VERSION 5.7 ;
BUSBITCHARS "[]" ;
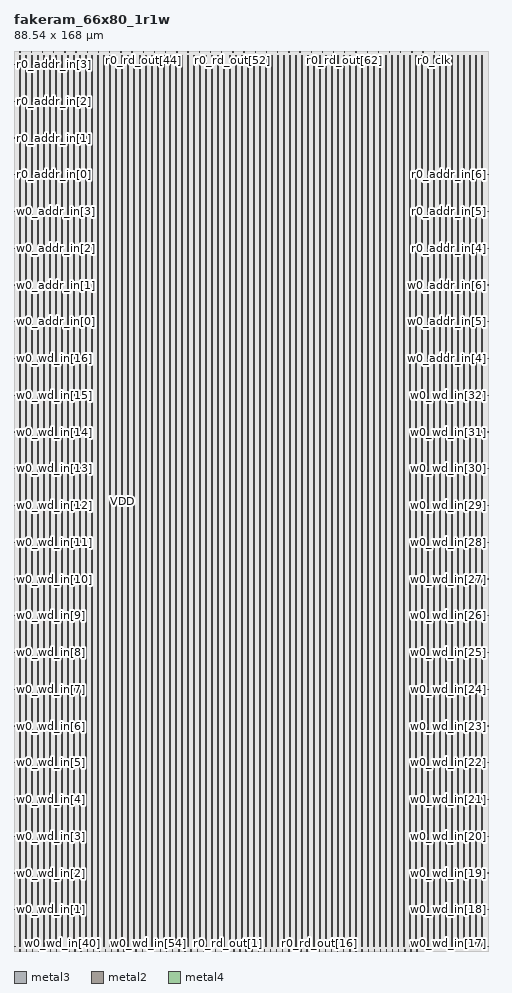
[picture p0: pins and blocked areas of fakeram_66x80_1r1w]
MACRO fakeram_66x80_1r1w
  FOREIGN fakeram_66x80_1r1w 0 0 ;
  SYMMETRY X Y R90 ;
  SIZE 88.540 BY 168.000 ;
  CLASS BLOCK ;
  PIN w0_wd_in[0]
    DIRECTION INPUT ;
    USE SIGNAL ;
    SHAPE ABUTMENT ;
    PORT
      LAYER metal3 ;
      RECT 0.000 0.805 0.210 0.875 ;
    END
  END w0_wd_in[0]
  PIN w0_wd_in[1]
    DIRECTION INPUT ;
    USE SIGNAL ;
    SHAPE ABUTMENT ;
    PORT
      LAYER metal3 ;
      RECT 0.000 7.665 0.210 7.735 ;
    END
  END w0_wd_in[1]
  PIN w0_wd_in[2]
    DIRECTION INPUT ;
    USE SIGNAL ;
    SHAPE ABUTMENT ;
    PORT
      LAYER metal3 ;
      RECT 0.000 14.525 0.210 14.595 ;
    END
  END w0_wd_in[2]
  PIN w0_wd_in[3]
    DIRECTION INPUT ;
    USE SIGNAL ;
    SHAPE ABUTMENT ;
    PORT
      LAYER metal3 ;
      RECT 0.000 21.385 0.210 21.455 ;
    END
  END w0_wd_in[3]
  PIN w0_wd_in[4]
    DIRECTION INPUT ;
    USE SIGNAL ;
    SHAPE ABUTMENT ;
    PORT
      LAYER metal3 ;
      RECT 0.000 28.245 0.210 28.315 ;
    END
  END w0_wd_in[4]
  PIN w0_wd_in[5]
    DIRECTION INPUT ;
    USE SIGNAL ;
    SHAPE ABUTMENT ;
    PORT
      LAYER metal3 ;
      RECT 0.000 35.105 0.210 35.175 ;
    END
  END w0_wd_in[5]
  PIN w0_wd_in[6]
    DIRECTION INPUT ;
    USE SIGNAL ;
    SHAPE ABUTMENT ;
    PORT
      LAYER metal3 ;
      RECT 0.000 41.965 0.210 42.035 ;
    END
  END w0_wd_in[6]
  PIN w0_wd_in[7]
    DIRECTION INPUT ;
    USE SIGNAL ;
    SHAPE ABUTMENT ;
    PORT
      LAYER metal3 ;
      RECT 0.000 48.825 0.210 48.895 ;
    END
  END w0_wd_in[7]
  PIN w0_wd_in[8]
    DIRECTION INPUT ;
    USE SIGNAL ;
    SHAPE ABUTMENT ;
    PORT
      LAYER metal3 ;
      RECT 0.000 55.685 0.210 55.755 ;
    END
  END w0_wd_in[8]
  PIN w0_wd_in[9]
    DIRECTION INPUT ;
    USE SIGNAL ;
    SHAPE ABUTMENT ;
    PORT
      LAYER metal3 ;
      RECT 0.000 62.545 0.210 62.615 ;
    END
  END w0_wd_in[9]
  PIN w0_wd_in[10]
    DIRECTION INPUT ;
    USE SIGNAL ;
    SHAPE ABUTMENT ;
    PORT
      LAYER metal3 ;
      RECT 0.000 69.405 0.210 69.475 ;
    END
  END w0_wd_in[10]
  PIN w0_wd_in[11]
    DIRECTION INPUT ;
    USE SIGNAL ;
    SHAPE ABUTMENT ;
    PORT
      LAYER metal3 ;
      RECT 0.000 76.265 0.210 76.335 ;
    END
  END w0_wd_in[11]
  PIN w0_wd_in[12]
    DIRECTION INPUT ;
    USE SIGNAL ;
    SHAPE ABUTMENT ;
    PORT
      LAYER metal3 ;
      RECT 0.000 83.125 0.210 83.195 ;
    END
  END w0_wd_in[12]
  PIN w0_wd_in[13]
    DIRECTION INPUT ;
    USE SIGNAL ;
    SHAPE ABUTMENT ;
    PORT
      LAYER metal3 ;
      RECT 0.000 89.985 0.210 90.055 ;
    END
  END w0_wd_in[13]
  PIN w0_wd_in[14]
    DIRECTION INPUT ;
    USE SIGNAL ;
    SHAPE ABUTMENT ;
    PORT
      LAYER metal3 ;
      RECT 0.000 96.845 0.210 96.915 ;
    END
  END w0_wd_in[14]
  PIN w0_wd_in[15]
    DIRECTION INPUT ;
    USE SIGNAL ;
    SHAPE ABUTMENT ;
    PORT
      LAYER metal3 ;
      RECT 0.000 103.705 0.210 103.775 ;
    END
  END w0_wd_in[15]
  PIN w0_wd_in[16]
    DIRECTION INPUT ;
    USE SIGNAL ;
    SHAPE ABUTMENT ;
    PORT
      LAYER metal3 ;
      RECT 0.000 110.565 0.210 110.635 ;
    END
  END w0_wd_in[16]
  PIN w0_wd_in[17]
    DIRECTION INPUT ;
    USE SIGNAL ;
    SHAPE ABUTMENT ;
    PORT
      LAYER metal3 ;
      RECT 88.330 0.805 88.540 0.875 ;
    END
  END w0_wd_in[17]
  PIN w0_wd_in[18]
    DIRECTION INPUT ;
    USE SIGNAL ;
    SHAPE ABUTMENT ;
    PORT
      LAYER metal3 ;
      RECT 88.330 7.665 88.540 7.735 ;
    END
  END w0_wd_in[18]
  PIN w0_wd_in[19]
    DIRECTION INPUT ;
    USE SIGNAL ;
    SHAPE ABUTMENT ;
    PORT
      LAYER metal3 ;
      RECT 88.330 14.525 88.540 14.595 ;
    END
  END w0_wd_in[19]
  PIN w0_wd_in[20]
    DIRECTION INPUT ;
    USE SIGNAL ;
    SHAPE ABUTMENT ;
    PORT
      LAYER metal3 ;
      RECT 88.330 21.385 88.540 21.455 ;
    END
  END w0_wd_in[20]
  PIN w0_wd_in[21]
    DIRECTION INPUT ;
    USE SIGNAL ;
    SHAPE ABUTMENT ;
    PORT
      LAYER metal3 ;
      RECT 88.330 28.245 88.540 28.315 ;
    END
  END w0_wd_in[21]
  PIN w0_wd_in[22]
    DIRECTION INPUT ;
    USE SIGNAL ;
    SHAPE ABUTMENT ;
    PORT
      LAYER metal3 ;
      RECT 88.330 35.105 88.540 35.175 ;
    END
  END w0_wd_in[22]
  PIN w0_wd_in[23]
    DIRECTION INPUT ;
    USE SIGNAL ;
    SHAPE ABUTMENT ;
    PORT
      LAYER metal3 ;
      RECT 88.330 41.965 88.540 42.035 ;
    END
  END w0_wd_in[23]
  PIN w0_wd_in[24]
    DIRECTION INPUT ;
    USE SIGNAL ;
    SHAPE ABUTMENT ;
    PORT
      LAYER metal3 ;
      RECT 88.330 48.825 88.540 48.895 ;
    END
  END w0_wd_in[24]
  PIN w0_wd_in[25]
    DIRECTION INPUT ;
    USE SIGNAL ;
    SHAPE ABUTMENT ;
    PORT
      LAYER metal3 ;
      RECT 88.330 55.685 88.540 55.755 ;
    END
  END w0_wd_in[25]
  PIN w0_wd_in[26]
    DIRECTION INPUT ;
    USE SIGNAL ;
    SHAPE ABUTMENT ;
    PORT
      LAYER metal3 ;
      RECT 88.330 62.545 88.540 62.615 ;
    END
  END w0_wd_in[26]
  PIN w0_wd_in[27]
    DIRECTION INPUT ;
    USE SIGNAL ;
    SHAPE ABUTMENT ;
    PORT
      LAYER metal3 ;
      RECT 88.330 69.405 88.540 69.475 ;
    END
  END w0_wd_in[27]
  PIN w0_wd_in[28]
    DIRECTION INPUT ;
    USE SIGNAL ;
    SHAPE ABUTMENT ;
    PORT
      LAYER metal3 ;
      RECT 88.330 76.265 88.540 76.335 ;
    END
  END w0_wd_in[28]
  PIN w0_wd_in[29]
    DIRECTION INPUT ;
    USE SIGNAL ;
    SHAPE ABUTMENT ;
    PORT
      LAYER metal3 ;
      RECT 88.330 83.125 88.540 83.195 ;
    END
  END w0_wd_in[29]
  PIN w0_wd_in[30]
    DIRECTION INPUT ;
    USE SIGNAL ;
    SHAPE ABUTMENT ;
    PORT
      LAYER metal3 ;
      RECT 88.330 89.985 88.540 90.055 ;
    END
  END w0_wd_in[30]
  PIN w0_wd_in[31]
    DIRECTION INPUT ;
    USE SIGNAL ;
    SHAPE ABUTMENT ;
    PORT
      LAYER metal3 ;
      RECT 88.330 96.845 88.540 96.915 ;
    END
  END w0_wd_in[31]
  PIN w0_wd_in[32]
    DIRECTION INPUT ;
    USE SIGNAL ;
    SHAPE ABUTMENT ;
    PORT
      LAYER metal3 ;
      RECT 88.330 103.705 88.540 103.775 ;
    END
  END w0_wd_in[32]
  PIN w0_wd_in[33]
    DIRECTION INPUT ;
    USE SIGNAL ;
    SHAPE ABUTMENT ;
    PORT
      LAYER metal2 ;
      RECT 1.105 0.000 1.175 0.210 ;
    END
  END w0_wd_in[33]
  PIN w0_wd_in[34]
    DIRECTION INPUT ;
    USE SIGNAL ;
    SHAPE ABUTMENT ;
    PORT
      LAYER metal2 ;
      RECT 2.245 0.000 2.315 0.210 ;
    END
  END w0_wd_in[34]
  PIN w0_wd_in[35]
    DIRECTION INPUT ;
    USE SIGNAL ;
    SHAPE ABUTMENT ;
    PORT
      LAYER metal2 ;
      RECT 3.385 0.000 3.455 0.210 ;
    END
  END w0_wd_in[35]
  PIN w0_wd_in[36]
    DIRECTION INPUT ;
    USE SIGNAL ;
    SHAPE ABUTMENT ;
    PORT
      LAYER metal2 ;
      RECT 4.525 0.000 4.595 0.210 ;
    END
  END w0_wd_in[36]
  PIN w0_wd_in[37]
    DIRECTION INPUT ;
    USE SIGNAL ;
    SHAPE ABUTMENT ;
    PORT
      LAYER metal2 ;
      RECT 5.665 0.000 5.735 0.210 ;
    END
  END w0_wd_in[37]
  PIN w0_wd_in[38]
    DIRECTION INPUT ;
    USE SIGNAL ;
    SHAPE ABUTMENT ;
    PORT
      LAYER metal2 ;
      RECT 6.805 0.000 6.875 0.210 ;
    END
  END w0_wd_in[38]
  PIN w0_wd_in[39]
    DIRECTION INPUT ;
    USE SIGNAL ;
    SHAPE ABUTMENT ;
    PORT
      LAYER metal2 ;
      RECT 7.945 0.000 8.015 0.210 ;
    END
  END w0_wd_in[39]
  PIN w0_wd_in[40]
    DIRECTION INPUT ;
    USE SIGNAL ;
    SHAPE ABUTMENT ;
    PORT
      LAYER metal2 ;
      RECT 9.085 0.000 9.155 0.210 ;
    END
  END w0_wd_in[40]
  PIN w0_wd_in[41]
    DIRECTION INPUT ;
    USE SIGNAL ;
    SHAPE ABUTMENT ;
    PORT
      LAYER metal2 ;
      RECT 10.225 0.000 10.295 0.210 ;
    END
  END w0_wd_in[41]
  PIN w0_wd_in[42]
    DIRECTION INPUT ;
    USE SIGNAL ;
    SHAPE ABUTMENT ;
    PORT
      LAYER metal2 ;
      RECT 11.365 0.000 11.435 0.210 ;
    END
  END w0_wd_in[42]
  PIN w0_wd_in[43]
    DIRECTION INPUT ;
    USE SIGNAL ;
    SHAPE ABUTMENT ;
    PORT
      LAYER metal2 ;
      RECT 12.505 0.000 12.575 0.210 ;
    END
  END w0_wd_in[43]
  PIN w0_wd_in[44]
    DIRECTION INPUT ;
    USE SIGNAL ;
    SHAPE ABUTMENT ;
    PORT
      LAYER metal2 ;
      RECT 13.645 0.000 13.715 0.210 ;
    END
  END w0_wd_in[44]
  PIN w0_wd_in[45]
    DIRECTION INPUT ;
    USE SIGNAL ;
    SHAPE ABUTMENT ;
    PORT
      LAYER metal2 ;
      RECT 14.785 0.000 14.855 0.210 ;
    END
  END w0_wd_in[45]
  PIN w0_wd_in[46]
    DIRECTION INPUT ;
    USE SIGNAL ;
    SHAPE ABUTMENT ;
    PORT
      LAYER metal2 ;
      RECT 15.925 0.000 15.995 0.210 ;
    END
  END w0_wd_in[46]
  PIN w0_wd_in[47]
    DIRECTION INPUT ;
    USE SIGNAL ;
    SHAPE ABUTMENT ;
    PORT
      LAYER metal2 ;
      RECT 17.065 0.000 17.135 0.210 ;
    END
  END w0_wd_in[47]
  PIN w0_wd_in[48]
    DIRECTION INPUT ;
    USE SIGNAL ;
    SHAPE ABUTMENT ;
    PORT
      LAYER metal2 ;
      RECT 18.205 0.000 18.275 0.210 ;
    END
  END w0_wd_in[48]
  PIN w0_wd_in[49]
    DIRECTION INPUT ;
    USE SIGNAL ;
    SHAPE ABUTMENT ;
    PORT
      LAYER metal2 ;
      RECT 19.345 0.000 19.415 0.210 ;
    END
  END w0_wd_in[49]
  PIN w0_wd_in[50]
    DIRECTION INPUT ;
    USE SIGNAL ;
    SHAPE ABUTMENT ;
    PORT
      LAYER metal2 ;
      RECT 20.485 0.000 20.555 0.210 ;
    END
  END w0_wd_in[50]
  PIN w0_wd_in[51]
    DIRECTION INPUT ;
    USE SIGNAL ;
    SHAPE ABUTMENT ;
    PORT
      LAYER metal2 ;
      RECT 21.625 0.000 21.695 0.210 ;
    END
  END w0_wd_in[51]
  PIN w0_wd_in[52]
    DIRECTION INPUT ;
    USE SIGNAL ;
    SHAPE ABUTMENT ;
    PORT
      LAYER metal2 ;
      RECT 22.765 0.000 22.835 0.210 ;
    END
  END w0_wd_in[52]
  PIN w0_wd_in[53]
    DIRECTION INPUT ;
    USE SIGNAL ;
    SHAPE ABUTMENT ;
    PORT
      LAYER metal2 ;
      RECT 23.905 0.000 23.975 0.210 ;
    END
  END w0_wd_in[53]
  PIN w0_wd_in[54]
    DIRECTION INPUT ;
    USE SIGNAL ;
    SHAPE ABUTMENT ;
    PORT
      LAYER metal2 ;
      RECT 25.045 0.000 25.115 0.210 ;
    END
  END w0_wd_in[54]
  PIN w0_wd_in[55]
    DIRECTION INPUT ;
    USE SIGNAL ;
    SHAPE ABUTMENT ;
    PORT
      LAYER metal2 ;
      RECT 26.185 0.000 26.255 0.210 ;
    END
  END w0_wd_in[55]
  PIN w0_wd_in[56]
    DIRECTION INPUT ;
    USE SIGNAL ;
    SHAPE ABUTMENT ;
    PORT
      LAYER metal2 ;
      RECT 27.325 0.000 27.395 0.210 ;
    END
  END w0_wd_in[56]
  PIN w0_wd_in[57]
    DIRECTION INPUT ;
    USE SIGNAL ;
    SHAPE ABUTMENT ;
    PORT
      LAYER metal2 ;
      RECT 28.465 0.000 28.535 0.210 ;
    END
  END w0_wd_in[57]
  PIN w0_wd_in[58]
    DIRECTION INPUT ;
    USE SIGNAL ;
    SHAPE ABUTMENT ;
    PORT
      LAYER metal2 ;
      RECT 29.605 0.000 29.675 0.210 ;
    END
  END w0_wd_in[58]
  PIN w0_wd_in[59]
    DIRECTION INPUT ;
    USE SIGNAL ;
    SHAPE ABUTMENT ;
    PORT
      LAYER metal2 ;
      RECT 30.745 0.000 30.815 0.210 ;
    END
  END w0_wd_in[59]
  PIN w0_wd_in[60]
    DIRECTION INPUT ;
    USE SIGNAL ;
    SHAPE ABUTMENT ;
    PORT
      LAYER metal2 ;
      RECT 31.885 0.000 31.955 0.210 ;
    END
  END w0_wd_in[60]
  PIN w0_wd_in[61]
    DIRECTION INPUT ;
    USE SIGNAL ;
    SHAPE ABUTMENT ;
    PORT
      LAYER metal2 ;
      RECT 33.025 0.000 33.095 0.210 ;
    END
  END w0_wd_in[61]
  PIN w0_wd_in[62]
    DIRECTION INPUT ;
    USE SIGNAL ;
    SHAPE ABUTMENT ;
    PORT
      LAYER metal2 ;
      RECT 34.165 0.000 34.235 0.210 ;
    END
  END w0_wd_in[62]
  PIN w0_wd_in[63]
    DIRECTION INPUT ;
    USE SIGNAL ;
    SHAPE ABUTMENT ;
    PORT
      LAYER metal2 ;
      RECT 35.305 0.000 35.375 0.210 ;
    END
  END w0_wd_in[63]
  PIN w0_wd_in[64]
    DIRECTION INPUT ;
    USE SIGNAL ;
    SHAPE ABUTMENT ;
    PORT
      LAYER metal2 ;
      RECT 36.445 0.000 36.515 0.210 ;
    END
  END w0_wd_in[64]
  PIN w0_wd_in[65]
    DIRECTION INPUT ;
    USE SIGNAL ;
    SHAPE ABUTMENT ;
    PORT
      LAYER metal2 ;
      RECT 37.585 0.000 37.655 0.210 ;
    END
  END w0_wd_in[65]
  PIN r0_rd_out[0]
    DIRECTION OUTPUT ;
    USE SIGNAL ;
    SHAPE ABUTMENT ;
    PORT
      LAYER metal2 ;
      RECT 38.725 0.000 38.795 0.210 ;
    END
  END r0_rd_out[0]
  PIN r0_rd_out[1]
    DIRECTION OUTPUT ;
    USE SIGNAL ;
    SHAPE ABUTMENT ;
    PORT
      LAYER metal2 ;
      RECT 39.865 0.000 39.935 0.210 ;
    END
  END r0_rd_out[1]
  PIN r0_rd_out[2]
    DIRECTION OUTPUT ;
    USE SIGNAL ;
    SHAPE ABUTMENT ;
    PORT
      LAYER metal2 ;
      RECT 41.005 0.000 41.075 0.210 ;
    END
  END r0_rd_out[2]
  PIN r0_rd_out[3]
    DIRECTION OUTPUT ;
    USE SIGNAL ;
    SHAPE ABUTMENT ;
    PORT
      LAYER metal2 ;
      RECT 42.145 0.000 42.215 0.210 ;
    END
  END r0_rd_out[3]
  PIN r0_rd_out[4]
    DIRECTION OUTPUT ;
    USE SIGNAL ;
    SHAPE ABUTMENT ;
    PORT
      LAYER metal2 ;
      RECT 43.285 0.000 43.355 0.210 ;
    END
  END r0_rd_out[4]
  PIN r0_rd_out[5]
    DIRECTION OUTPUT ;
    USE SIGNAL ;
    SHAPE ABUTMENT ;
    PORT
      LAYER metal2 ;
      RECT 44.425 0.000 44.495 0.210 ;
    END
  END r0_rd_out[5]
  PIN r0_rd_out[6]
    DIRECTION OUTPUT ;
    USE SIGNAL ;
    SHAPE ABUTMENT ;
    PORT
      LAYER metal2 ;
      RECT 45.565 0.000 45.635 0.210 ;
    END
  END r0_rd_out[6]
  PIN r0_rd_out[7]
    DIRECTION OUTPUT ;
    USE SIGNAL ;
    SHAPE ABUTMENT ;
    PORT
      LAYER metal2 ;
      RECT 46.705 0.000 46.775 0.210 ;
    END
  END r0_rd_out[7]
  PIN r0_rd_out[8]
    DIRECTION OUTPUT ;
    USE SIGNAL ;
    SHAPE ABUTMENT ;
    PORT
      LAYER metal2 ;
      RECT 47.845 0.000 47.915 0.210 ;
    END
  END r0_rd_out[8]
  PIN r0_rd_out[9]
    DIRECTION OUTPUT ;
    USE SIGNAL ;
    SHAPE ABUTMENT ;
    PORT
      LAYER metal2 ;
      RECT 48.985 0.000 49.055 0.210 ;
    END
  END r0_rd_out[9]
  PIN r0_rd_out[10]
    DIRECTION OUTPUT ;
    USE SIGNAL ;
    SHAPE ABUTMENT ;
    PORT
      LAYER metal2 ;
      RECT 50.125 0.000 50.195 0.210 ;
    END
  END r0_rd_out[10]
  PIN r0_rd_out[11]
    DIRECTION OUTPUT ;
    USE SIGNAL ;
    SHAPE ABUTMENT ;
    PORT
      LAYER metal2 ;
      RECT 51.265 0.000 51.335 0.210 ;
    END
  END r0_rd_out[11]
  PIN r0_rd_out[12]
    DIRECTION OUTPUT ;
    USE SIGNAL ;
    SHAPE ABUTMENT ;
    PORT
      LAYER metal2 ;
      RECT 52.405 0.000 52.475 0.210 ;
    END
  END r0_rd_out[12]
  PIN r0_rd_out[13]
    DIRECTION OUTPUT ;
    USE SIGNAL ;
    SHAPE ABUTMENT ;
    PORT
      LAYER metal2 ;
      RECT 53.545 0.000 53.615 0.210 ;
    END
  END r0_rd_out[13]
  PIN r0_rd_out[14]
    DIRECTION OUTPUT ;
    USE SIGNAL ;
    SHAPE ABUTMENT ;
    PORT
      LAYER metal2 ;
      RECT 54.685 0.000 54.755 0.210 ;
    END
  END r0_rd_out[14]
  PIN r0_rd_out[15]
    DIRECTION OUTPUT ;
    USE SIGNAL ;
    SHAPE ABUTMENT ;
    PORT
      LAYER metal2 ;
      RECT 55.825 0.000 55.895 0.210 ;
    END
  END r0_rd_out[15]
  PIN r0_rd_out[16]
    DIRECTION OUTPUT ;
    USE SIGNAL ;
    SHAPE ABUTMENT ;
    PORT
      LAYER metal2 ;
      RECT 56.965 0.000 57.035 0.210 ;
    END
  END r0_rd_out[16]
  PIN r0_rd_out[17]
    DIRECTION OUTPUT ;
    USE SIGNAL ;
    SHAPE ABUTMENT ;
    PORT
      LAYER metal2 ;
      RECT 58.105 0.000 58.175 0.210 ;
    END
  END r0_rd_out[17]
  PIN r0_rd_out[18]
    DIRECTION OUTPUT ;
    USE SIGNAL ;
    SHAPE ABUTMENT ;
    PORT
      LAYER metal2 ;
      RECT 59.245 0.000 59.315 0.210 ;
    END
  END r0_rd_out[18]
  PIN r0_rd_out[19]
    DIRECTION OUTPUT ;
    USE SIGNAL ;
    SHAPE ABUTMENT ;
    PORT
      LAYER metal2 ;
      RECT 60.385 0.000 60.455 0.210 ;
    END
  END r0_rd_out[19]
  PIN r0_rd_out[20]
    DIRECTION OUTPUT ;
    USE SIGNAL ;
    SHAPE ABUTMENT ;
    PORT
      LAYER metal2 ;
      RECT 61.525 0.000 61.595 0.210 ;
    END
  END r0_rd_out[20]
  PIN r0_rd_out[21]
    DIRECTION OUTPUT ;
    USE SIGNAL ;
    SHAPE ABUTMENT ;
    PORT
      LAYER metal2 ;
      RECT 62.665 0.000 62.735 0.210 ;
    END
  END r0_rd_out[21]
  PIN r0_rd_out[22]
    DIRECTION OUTPUT ;
    USE SIGNAL ;
    SHAPE ABUTMENT ;
    PORT
      LAYER metal2 ;
      RECT 63.805 0.000 63.875 0.210 ;
    END
  END r0_rd_out[22]
  PIN r0_rd_out[23]
    DIRECTION OUTPUT ;
    USE SIGNAL ;
    SHAPE ABUTMENT ;
    PORT
      LAYER metal2 ;
      RECT 64.945 0.000 65.015 0.210 ;
    END
  END r0_rd_out[23]
  PIN r0_rd_out[24]
    DIRECTION OUTPUT ;
    USE SIGNAL ;
    SHAPE ABUTMENT ;
    PORT
      LAYER metal2 ;
      RECT 66.085 0.000 66.155 0.210 ;
    END
  END r0_rd_out[24]
  PIN r0_rd_out[25]
    DIRECTION OUTPUT ;
    USE SIGNAL ;
    SHAPE ABUTMENT ;
    PORT
      LAYER metal2 ;
      RECT 67.225 0.000 67.295 0.210 ;
    END
  END r0_rd_out[25]
  PIN r0_rd_out[26]
    DIRECTION OUTPUT ;
    USE SIGNAL ;
    SHAPE ABUTMENT ;
    PORT
      LAYER metal2 ;
      RECT 68.365 0.000 68.435 0.210 ;
    END
  END r0_rd_out[26]
  PIN r0_rd_out[27]
    DIRECTION OUTPUT ;
    USE SIGNAL ;
    SHAPE ABUTMENT ;
    PORT
      LAYER metal2 ;
      RECT 69.505 0.000 69.575 0.210 ;
    END
  END r0_rd_out[27]
  PIN r0_rd_out[28]
    DIRECTION OUTPUT ;
    USE SIGNAL ;
    SHAPE ABUTMENT ;
    PORT
      LAYER metal2 ;
      RECT 70.645 0.000 70.715 0.210 ;
    END
  END r0_rd_out[28]
  PIN r0_rd_out[29]
    DIRECTION OUTPUT ;
    USE SIGNAL ;
    SHAPE ABUTMENT ;
    PORT
      LAYER metal2 ;
      RECT 71.785 0.000 71.855 0.210 ;
    END
  END r0_rd_out[29]
  PIN r0_rd_out[30]
    DIRECTION OUTPUT ;
    USE SIGNAL ;
    SHAPE ABUTMENT ;
    PORT
      LAYER metal2 ;
      RECT 72.925 0.000 72.995 0.210 ;
    END
  END r0_rd_out[30]
  PIN r0_rd_out[31]
    DIRECTION OUTPUT ;
    USE SIGNAL ;
    SHAPE ABUTMENT ;
    PORT
      LAYER metal2 ;
      RECT 74.065 0.000 74.135 0.210 ;
    END
  END r0_rd_out[31]
  PIN r0_rd_out[32]
    DIRECTION OUTPUT ;
    USE SIGNAL ;
    SHAPE ABUTMENT ;
    PORT
      LAYER metal2 ;
      RECT 75.205 0.000 75.275 0.210 ;
    END
  END r0_rd_out[32]
  PIN r0_rd_out[33]
    DIRECTION OUTPUT ;
    USE SIGNAL ;
    SHAPE ABUTMENT ;
    PORT
      LAYER metal2 ;
      RECT 1.105 167.790 1.175 168.000 ;
    END
  END r0_rd_out[33]
  PIN r0_rd_out[34]
    DIRECTION OUTPUT ;
    USE SIGNAL ;
    SHAPE ABUTMENT ;
    PORT
      LAYER metal2 ;
      RECT 3.195 167.790 3.265 168.000 ;
    END
  END r0_rd_out[34]
  PIN r0_rd_out[35]
    DIRECTION OUTPUT ;
    USE SIGNAL ;
    SHAPE ABUTMENT ;
    PORT
      LAYER metal2 ;
      RECT 5.285 167.790 5.355 168.000 ;
    END
  END r0_rd_out[35]
  PIN r0_rd_out[36]
    DIRECTION OUTPUT ;
    USE SIGNAL ;
    SHAPE ABUTMENT ;
    PORT
      LAYER metal2 ;
      RECT 7.375 167.790 7.445 168.000 ;
    END
  END r0_rd_out[36]
  PIN r0_rd_out[37]
    DIRECTION OUTPUT ;
    USE SIGNAL ;
    SHAPE ABUTMENT ;
    PORT
      LAYER metal2 ;
      RECT 9.465 167.790 9.535 168.000 ;
    END
  END r0_rd_out[37]
  PIN r0_rd_out[38]
    DIRECTION OUTPUT ;
    USE SIGNAL ;
    SHAPE ABUTMENT ;
    PORT
      LAYER metal2 ;
      RECT 11.555 167.790 11.625 168.000 ;
    END
  END r0_rd_out[38]
  PIN r0_rd_out[39]
    DIRECTION OUTPUT ;
    USE SIGNAL ;
    SHAPE ABUTMENT ;
    PORT
      LAYER metal2 ;
      RECT 13.645 167.790 13.715 168.000 ;
    END
  END r0_rd_out[39]
  PIN r0_rd_out[40]
    DIRECTION OUTPUT ;
    USE SIGNAL ;
    SHAPE ABUTMENT ;
    PORT
      LAYER metal2 ;
      RECT 15.735 167.790 15.805 168.000 ;
    END
  END r0_rd_out[40]
  PIN r0_rd_out[41]
    DIRECTION OUTPUT ;
    USE SIGNAL ;
    SHAPE ABUTMENT ;
    PORT
      LAYER metal2 ;
      RECT 17.825 167.790 17.895 168.000 ;
    END
  END r0_rd_out[41]
  PIN r0_rd_out[42]
    DIRECTION OUTPUT ;
    USE SIGNAL ;
    SHAPE ABUTMENT ;
    PORT
      LAYER metal2 ;
      RECT 19.915 167.790 19.985 168.000 ;
    END
  END r0_rd_out[42]
  PIN r0_rd_out[43]
    DIRECTION OUTPUT ;
    USE SIGNAL ;
    SHAPE ABUTMENT ;
    PORT
      LAYER metal2 ;
      RECT 22.005 167.790 22.075 168.000 ;
    END
  END r0_rd_out[43]
  PIN r0_rd_out[44]
    DIRECTION OUTPUT ;
    USE SIGNAL ;
    SHAPE ABUTMENT ;
    PORT
      LAYER metal2 ;
      RECT 24.095 167.790 24.165 168.000 ;
    END
  END r0_rd_out[44]
  PIN r0_rd_out[45]
    DIRECTION OUTPUT ;
    USE SIGNAL ;
    SHAPE ABUTMENT ;
    PORT
      LAYER metal2 ;
      RECT 26.185 167.790 26.255 168.000 ;
    END
  END r0_rd_out[45]
  PIN r0_rd_out[46]
    DIRECTION OUTPUT ;
    USE SIGNAL ;
    SHAPE ABUTMENT ;
    PORT
      LAYER metal2 ;
      RECT 28.275 167.790 28.345 168.000 ;
    END
  END r0_rd_out[46]
  PIN r0_rd_out[47]
    DIRECTION OUTPUT ;
    USE SIGNAL ;
    SHAPE ABUTMENT ;
    PORT
      LAYER metal2 ;
      RECT 30.365 167.790 30.435 168.000 ;
    END
  END r0_rd_out[47]
  PIN r0_rd_out[48]
    DIRECTION OUTPUT ;
    USE SIGNAL ;
    SHAPE ABUTMENT ;
    PORT
      LAYER metal2 ;
      RECT 32.455 167.790 32.525 168.000 ;
    END
  END r0_rd_out[48]
  PIN r0_rd_out[49]
    DIRECTION OUTPUT ;
    USE SIGNAL ;
    SHAPE ABUTMENT ;
    PORT
      LAYER metal2 ;
      RECT 34.545 167.790 34.615 168.000 ;
    END
  END r0_rd_out[49]
  PIN r0_rd_out[50]
    DIRECTION OUTPUT ;
    USE SIGNAL ;
    SHAPE ABUTMENT ;
    PORT
      LAYER metal2 ;
      RECT 36.635 167.790 36.705 168.000 ;
    END
  END r0_rd_out[50]
  PIN r0_rd_out[51]
    DIRECTION OUTPUT ;
    USE SIGNAL ;
    SHAPE ABUTMENT ;
    PORT
      LAYER metal2 ;
      RECT 38.725 167.790 38.795 168.000 ;
    END
  END r0_rd_out[51]
  PIN r0_rd_out[52]
    DIRECTION OUTPUT ;
    USE SIGNAL ;
    SHAPE ABUTMENT ;
    PORT
      LAYER metal2 ;
      RECT 40.815 167.790 40.885 168.000 ;
    END
  END r0_rd_out[52]
  PIN r0_rd_out[53]
    DIRECTION OUTPUT ;
    USE SIGNAL ;
    SHAPE ABUTMENT ;
    PORT
      LAYER metal2 ;
      RECT 42.905 167.790 42.975 168.000 ;
    END
  END r0_rd_out[53]
  PIN r0_rd_out[54]
    DIRECTION OUTPUT ;
    USE SIGNAL ;
    SHAPE ABUTMENT ;
    PORT
      LAYER metal2 ;
      RECT 44.995 167.790 45.065 168.000 ;
    END
  END r0_rd_out[54]
  PIN r0_rd_out[55]
    DIRECTION OUTPUT ;
    USE SIGNAL ;
    SHAPE ABUTMENT ;
    PORT
      LAYER metal2 ;
      RECT 47.085 167.790 47.155 168.000 ;
    END
  END r0_rd_out[55]
  PIN r0_rd_out[56]
    DIRECTION OUTPUT ;
    USE SIGNAL ;
    SHAPE ABUTMENT ;
    PORT
      LAYER metal2 ;
      RECT 49.175 167.790 49.245 168.000 ;
    END
  END r0_rd_out[56]
  PIN r0_rd_out[57]
    DIRECTION OUTPUT ;
    USE SIGNAL ;
    SHAPE ABUTMENT ;
    PORT
      LAYER metal2 ;
      RECT 51.265 167.790 51.335 168.000 ;
    END
  END r0_rd_out[57]
  PIN r0_rd_out[58]
    DIRECTION OUTPUT ;
    USE SIGNAL ;
    SHAPE ABUTMENT ;
    PORT
      LAYER metal2 ;
      RECT 53.355 167.790 53.425 168.000 ;
    END
  END r0_rd_out[58]
  PIN r0_rd_out[59]
    DIRECTION OUTPUT ;
    USE SIGNAL ;
    SHAPE ABUTMENT ;
    PORT
      LAYER metal2 ;
      RECT 55.445 167.790 55.515 168.000 ;
    END
  END r0_rd_out[59]
  PIN r0_rd_out[60]
    DIRECTION OUTPUT ;
    USE SIGNAL ;
    SHAPE ABUTMENT ;
    PORT
      LAYER metal2 ;
      RECT 57.535 167.790 57.605 168.000 ;
    END
  END r0_rd_out[60]
  PIN r0_rd_out[61]
    DIRECTION OUTPUT ;
    USE SIGNAL ;
    SHAPE ABUTMENT ;
    PORT
      LAYER metal2 ;
      RECT 59.625 167.790 59.695 168.000 ;
    END
  END r0_rd_out[61]
  PIN r0_rd_out[62]
    DIRECTION OUTPUT ;
    USE SIGNAL ;
    SHAPE ABUTMENT ;
    PORT
      LAYER metal2 ;
      RECT 61.715 167.790 61.785 168.000 ;
    END
  END r0_rd_out[62]
  PIN r0_rd_out[63]
    DIRECTION OUTPUT ;
    USE SIGNAL ;
    SHAPE ABUTMENT ;
    PORT
      LAYER metal2 ;
      RECT 63.805 167.790 63.875 168.000 ;
    END
  END r0_rd_out[63]
  PIN r0_rd_out[64]
    DIRECTION OUTPUT ;
    USE SIGNAL ;
    SHAPE ABUTMENT ;
    PORT
      LAYER metal2 ;
      RECT 65.895 167.790 65.965 168.000 ;
    END
  END r0_rd_out[64]
  PIN r0_rd_out[65]
    DIRECTION OUTPUT ;
    USE SIGNAL ;
    SHAPE ABUTMENT ;
    PORT
      LAYER metal2 ;
      RECT 67.985 167.790 68.055 168.000 ;
    END
  END r0_rd_out[65]
  PIN w0_addr_in[0]
    DIRECTION INPUT ;
    USE SIGNAL ;
    SHAPE ABUTMENT ;
    PORT
      LAYER metal3 ;
      RECT 0.000 117.425 0.210 117.495 ;
    END
  END w0_addr_in[0]
  PIN w0_addr_in[1]
    DIRECTION INPUT ;
    USE SIGNAL ;
    SHAPE ABUTMENT ;
    PORT
      LAYER metal3 ;
      RECT 0.000 124.285 0.210 124.355 ;
    END
  END w0_addr_in[1]
  PIN w0_addr_in[2]
    DIRECTION INPUT ;
    USE SIGNAL ;
    SHAPE ABUTMENT ;
    PORT
      LAYER metal3 ;
      RECT 0.000 131.145 0.210 131.215 ;
    END
  END w0_addr_in[2]
  PIN w0_addr_in[3]
    DIRECTION INPUT ;
    USE SIGNAL ;
    SHAPE ABUTMENT ;
    PORT
      LAYER metal3 ;
      RECT 0.000 138.005 0.210 138.075 ;
    END
  END w0_addr_in[3]
  PIN w0_addr_in[4]
    DIRECTION INPUT ;
    USE SIGNAL ;
    SHAPE ABUTMENT ;
    PORT
      LAYER metal3 ;
      RECT 88.330 110.565 88.540 110.635 ;
    END
  END w0_addr_in[4]
  PIN w0_addr_in[5]
    DIRECTION INPUT ;
    USE SIGNAL ;
    SHAPE ABUTMENT ;
    PORT
      LAYER metal3 ;
      RECT 88.330 117.425 88.540 117.495 ;
    END
  END w0_addr_in[5]
  PIN w0_addr_in[6]
    DIRECTION INPUT ;
    USE SIGNAL ;
    SHAPE ABUTMENT ;
    PORT
      LAYER metal3 ;
      RECT 88.330 124.285 88.540 124.355 ;
    END
  END w0_addr_in[6]
  PIN r0_addr_in[0]
    DIRECTION INPUT ;
    USE SIGNAL ;
    SHAPE ABUTMENT ;
    PORT
      LAYER metal3 ;
      RECT 0.000 144.865 0.210 144.935 ;
    END
  END r0_addr_in[0]
  PIN r0_addr_in[1]
    DIRECTION INPUT ;
    USE SIGNAL ;
    SHAPE ABUTMENT ;
    PORT
      LAYER metal3 ;
      RECT 0.000 151.725 0.210 151.795 ;
    END
  END r0_addr_in[1]
  PIN r0_addr_in[2]
    DIRECTION INPUT ;
    USE SIGNAL ;
    SHAPE ABUTMENT ;
    PORT
      LAYER metal3 ;
      RECT 0.000 158.585 0.210 158.655 ;
    END
  END r0_addr_in[2]
  PIN r0_addr_in[3]
    DIRECTION INPUT ;
    USE SIGNAL ;
    SHAPE ABUTMENT ;
    PORT
      LAYER metal3 ;
      RECT 0.000 165.445 0.210 165.515 ;
    END
  END r0_addr_in[3]
  PIN r0_addr_in[4]
    DIRECTION INPUT ;
    USE SIGNAL ;
    SHAPE ABUTMENT ;
    PORT
      LAYER metal3 ;
      RECT 88.330 131.145 88.540 131.215 ;
    END
  END r0_addr_in[4]
  PIN r0_addr_in[5]
    DIRECTION INPUT ;
    USE SIGNAL ;
    SHAPE ABUTMENT ;
    PORT
      LAYER metal3 ;
      RECT 88.330 138.005 88.540 138.075 ;
    END
  END r0_addr_in[5]
  PIN r0_addr_in[6]
    DIRECTION INPUT ;
    USE SIGNAL ;
    SHAPE ABUTMENT ;
    PORT
      LAYER metal3 ;
      RECT 88.330 144.865 88.540 144.935 ;
    END
  END r0_addr_in[6]
  PIN w0_we_in
    DIRECTION INPUT ;
    USE SIGNAL ;
    SHAPE ABUTMENT ;
    PORT
      LAYER metal2 ;
      RECT 70.075 167.790 70.145 168.000 ;
    END
  END w0_we_in
  PIN w0_ce_in
    DIRECTION INPUT ;
    USE SIGNAL ;
    SHAPE ABUTMENT ;
    PORT
      LAYER metal2 ;
      RECT 72.165 167.790 72.235 168.000 ;
    END
  END w0_ce_in
  PIN w0_clk
    DIRECTION INPUT ;
    USE SIGNAL ;
    SHAPE ABUTMENT ;
    PORT
      LAYER metal2 ;
      RECT 74.255 167.790 74.325 168.000 ;
    END
  END w0_clk
  PIN r0_ce_in
    DIRECTION INPUT ;
    USE SIGNAL ;
    SHAPE ABUTMENT ;
    PORT
      LAYER metal2 ;
      RECT 76.345 167.790 76.415 168.000 ;
    END
  END r0_ce_in
  PIN r0_clk
    DIRECTION INPUT ;
    USE SIGNAL ;
    SHAPE ABUTMENT ;
    PORT
      LAYER metal2 ;
      RECT 78.435 167.790 78.505 168.000 ;
    END
  END r0_clk
  PIN VSS
    DIRECTION INOUT ;
    USE GROUND ;
    PORT
      LAYER metal4 ;
      RECT 1.000 0.840 1.280 167.160 ;
      RECT 3.240 0.840 3.520 167.160 ;
      RECT 5.480 0.840 5.760 167.160 ;
      RECT 7.720 0.840 8.000 167.160 ;
      RECT 9.960 0.840 10.240 167.160 ;
      RECT 12.200 0.840 12.480 167.160 ;
      RECT 14.440 0.840 14.720 167.160 ;
      RECT 16.680 0.840 16.960 167.160 ;
      RECT 18.920 0.840 19.200 167.160 ;
      RECT 21.160 0.840 21.440 167.160 ;
      RECT 23.400 0.840 23.680 167.160 ;
      RECT 25.640 0.840 25.920 167.160 ;
      RECT 27.880 0.840 28.160 167.160 ;
      RECT 30.120 0.840 30.400 167.160 ;
      RECT 32.360 0.840 32.640 167.160 ;
      RECT 34.600 0.840 34.880 167.160 ;
      RECT 36.840 0.840 37.120 167.160 ;
      RECT 39.080 0.840 39.360 167.160 ;
      RECT 41.320 0.840 41.600 167.160 ;
      RECT 43.560 0.840 43.840 167.160 ;
      RECT 45.800 0.840 46.080 167.160 ;
      RECT 48.040 0.840 48.320 167.160 ;
      RECT 50.280 0.840 50.560 167.160 ;
      RECT 52.520 0.840 52.800 167.160 ;
      RECT 54.760 0.840 55.040 167.160 ;
      RECT 57.000 0.840 57.280 167.160 ;
      RECT 59.240 0.840 59.520 167.160 ;
      RECT 61.480 0.840 61.760 167.160 ;
      RECT 63.720 0.840 64.000 167.160 ;
      RECT 65.960 0.840 66.240 167.160 ;
      RECT 68.200 0.840 68.480 167.160 ;
      RECT 70.440 0.840 70.720 167.160 ;
      RECT 72.680 0.840 72.960 167.160 ;
      RECT 74.920 0.840 75.200 167.160 ;
      RECT 77.160 0.840 77.440 167.160 ;
      RECT 79.400 0.840 79.680 167.160 ;
      RECT 81.640 0.840 81.920 167.160 ;
      RECT 83.880 0.840 84.160 167.160 ;
      RECT 86.120 0.840 86.400 167.160 ;
    END
  END VSS
  PIN VDD
    DIRECTION INOUT ;
    USE POWER ;
    PORT
      LAYER metal4 ;
      RECT 2.120 0.840 2.400 167.160 ;
      RECT 4.360 0.840 4.640 167.160 ;
      RECT 6.600 0.840 6.880 167.160 ;
      RECT 8.840 0.840 9.120 167.160 ;
      RECT 11.080 0.840 11.360 167.160 ;
      RECT 13.320 0.840 13.600 167.160 ;
      RECT 15.560 0.840 15.840 167.160 ;
      RECT 17.800 0.840 18.080 167.160 ;
      RECT 20.040 0.840 20.320 167.160 ;
      RECT 22.280 0.840 22.560 167.160 ;
      RECT 24.520 0.840 24.800 167.160 ;
      RECT 26.760 0.840 27.040 167.160 ;
      RECT 29.000 0.840 29.280 167.160 ;
      RECT 31.240 0.840 31.520 167.160 ;
      RECT 33.480 0.840 33.760 167.160 ;
      RECT 35.720 0.840 36.000 167.160 ;
      RECT 37.960 0.840 38.240 167.160 ;
      RECT 40.200 0.840 40.480 167.160 ;
      RECT 42.440 0.840 42.720 167.160 ;
      RECT 44.680 0.840 44.960 167.160 ;
      RECT 46.920 0.840 47.200 167.160 ;
      RECT 49.160 0.840 49.440 167.160 ;
      RECT 51.400 0.840 51.680 167.160 ;
      RECT 53.640 0.840 53.920 167.160 ;
      RECT 55.880 0.840 56.160 167.160 ;
      RECT 58.120 0.840 58.400 167.160 ;
      RECT 60.360 0.840 60.640 167.160 ;
      RECT 62.600 0.840 62.880 167.160 ;
      RECT 64.840 0.840 65.120 167.160 ;
      RECT 67.080 0.840 67.360 167.160 ;
      RECT 69.320 0.840 69.600 167.160 ;
      RECT 71.560 0.840 71.840 167.160 ;
      RECT 73.800 0.840 74.080 167.160 ;
      RECT 76.040 0.840 76.320 167.160 ;
      RECT 78.280 0.840 78.560 167.160 ;
      RECT 80.520 0.840 80.800 167.160 ;
      RECT 82.760 0.840 83.040 167.160 ;
      RECT 85.000 0.840 85.280 167.160 ;
      RECT 87.240 0.840 87.520 167.160 ;
    END
  END VDD
  OBS
    LAYER metal1 ;
    RECT 0 0 88.540 168.000 ;
    LAYER metal2 ;
    RECT 0 0 88.540 168.000 ;
    LAYER metal3 ;
    RECT 0 0 88.540 168.000 ;
    LAYER metal4 ;
    RECT 0 0 88.540 168.000 ;
    LAYER OVERLAP ;
    RECT 0 0 88.540 168.000 ;
  END
END fakeram_66x80_1r1w

END LIBRARY
